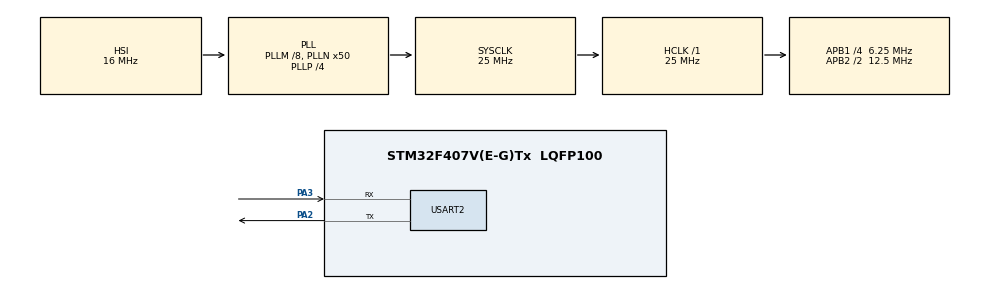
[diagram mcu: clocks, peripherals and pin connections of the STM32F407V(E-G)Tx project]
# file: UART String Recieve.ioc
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Mcu.Family=STM32F4
Mcu.Name=STM32F407V(E-G)Tx
Mcu.Package=LQFP100
NVIC.PriorityGroup=NVIC_PRIORITYGROUP_0
PA2.Mode=Asynchronous
PA2.Signal=USART2_TX
PA3.Mode=Asynchronous
PA3.Signal=USART2_RX
ProjectManager.HeapSize=0x200
ProjectManager.StackSize=0x400
ProjectManager.TargetToolchain=STM32CubeIDE
RCC.48MHZClocksFreq_Value=14285714.285714285
RCC.AHBFreq_Value=25000000
RCC.APB1CLKDivider=RCC_HCLK_DIV4
RCC.APB1Freq_Value=6250000
RCC.APB1TimFreq_Value=12500000
RCC.APB2CLKDivider=RCC_HCLK_DIV2
RCC.APB2Freq_Value=12500000
RCC.APB2TimFreq_Value=25000000
RCC.CortexFreq_Value=25000000
RCC.HCLKFreq_Value=25000000
RCC.HSE_VALUE=8000000
RCC.HSI_VALUE=16000000
RCC.LSE_VALUE=32768
RCC.PLLM=8
RCC.PLLN=50
RCC.PLLP=RCC_PLLP_DIV4
RCC.PLLQ=7
RCC.SYSCLKFreq_VALUE=25000000
RCC.SYSCLKSource=RCC_SYSCLKSOURCE_PLLCLK
RCC.VCOOutputFreq_Value=100000000
USART2.VirtualMode=VM_ASYNC
board=STM32F407G-DISC1

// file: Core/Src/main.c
/* USER CODE BEGIN Header */
/**
  ******************************************************************************
  * @file           : main.c
  * @brief          : Main program body
  ******************************************************************************
  * @attention
  *
  * Copyright (c) 2025 STMicroelectronics.
  * All rights reserved.
  *
  * This software is licensed under terms that can be found in the LICENSE file
  * in the root directory of this software component.
  * If no LICENSE file comes with this software, it is provided AS-IS.
  *
  ******************************************************************************
  */
/* USER CODE END Header */
#include "main.h"
#include<string.h>

/* USER CODE BEGIN Includes */

#define MAX_LEN 100
uint8_t rx_byte;             // single incoming byte
char rx_buffer[MAX_LEN];     // store full string
uint16_t rx_index = 0;       // current position

/* USER CODE END Includes */

UART_HandleTypeDef huart2;

void SystemClock_Config(void);
static void MX_GPIO_Init(void);
static void MX_USART2_UART_Init(void);

int main(void)
{

  /* MCU Configuration--------------------------------------------------------*/

  /* Reset of all peripherals, Initializes the Flash interface and the Systick. */
  HAL_Init();

  /* Configure the system clock */
  SystemClock_Config();

  /* Initialize all configured peripherals */
  MX_GPIO_Init();
  MX_USART2_UART_Init();
  /* USER CODE BEGIN 2 */
  char msg[50] = "Enter Data ...\r\n";
  HAL_UART_Transmit(&huart2, ( uint8_t *)msg,strlen(msg),HAL_MAX_DELAY);
  /* USER CODE END 2 */

  /* Infinite loop */
  /* USER CODE BEGIN WHILE */
  while (1)
  {
      /* Receive one byte (blocking polling) */
      HAL_UART_Receive(&huart2, &rx_byte, 1, HAL_MAX_DELAY);

      /* Echo received byte */
      HAL_UART_Transmit(&huart2, &rx_byte, 1, HAL_MAX_DELAY);

      /* ENTER key handling */
      if (rx_byte == '\r')
      {
          rx_buffer[rx_index] = '\0';   // terminate string

          char msg1[] = "\r\nYou sent: ";
          HAL_UART_Transmit(&huart2, (uint8_t*)msg1, strlen(msg1), HAL_MAX_DELAY);
          HAL_UART_Transmit(&huart2, (uint8_t*)rx_buffer, strlen(rx_buffer), HAL_MAX_DELAY);

          /* Convert to uppercase */
          strupr(rx_buffer);

//          char msg2[] = "\r\nUppercase: ";
//          HAL_UART_Transmit(&huart2, (uint8_t*)msg2, strlen(msg2), HAL_MAX_DELAY);
//          HAL_UART_Transmit(&huart2, (uint8_t*)rx_buffer, strlen(rx_buffer), HAL_MAX_DELAY);

//          uint8_t len = strlen(msg);
//          sprintf(msg, "len = %d\r\n", len);
//          HAL_UART_Transmit(&huart2, (uint8_t *)msg, strlen(msg), HAL_MAX_DELAY);

          char msg3[] = "\r\n";
          HAL_UART_Transmit(&huart2, (uint8_t*)msg3, strlen(msg3), HAL_MAX_DELAY);

          rx_index = 0;   // reset buffer
      }
      else
      {
          /* Store character */
          if (rx_index < MAX_LEN - 1)
          {
              rx_buffer[rx_index++] = rx_byte;
          }
      }
  }

  /* USER CODE END 3 */
}

void SystemClock_Config(void)
{
  RCC_OscInitTypeDef RCC_OscInitStruct = {0};
  RCC_ClkInitTypeDef RCC_ClkInitStruct = {0};

  /** Configure the main internal regulator output voltage
  */
  __HAL_RCC_PWR_CLK_ENABLE();
  __HAL_PWR_VOLTAGESCALING_CONFIG(PWR_REGULATOR_VOLTAGE_SCALE1);

  /** Initializes the RCC Oscillators according to the specified parameters
  * in the RCC_OscInitTypeDef structure.
  */
  RCC_OscInitStruct.OscillatorType = RCC_OSCILLATORTYPE_HSI;
  RCC_OscInitStruct.HSIState = RCC_HSI_ON;
  RCC_OscInitStruct.HSICalibrationValue = RCC_HSICALIBRATION_DEFAULT;
  RCC_OscInitStruct.PLL.PLLState = RCC_PLL_ON;
  RCC_OscInitStruct.PLL.PLLSource = RCC_PLLSOURCE_HSI;
  RCC_OscInitStruct.PLL.PLLM = 8;
  RCC_OscInitStruct.PLL.PLLN = 50;
  RCC_OscInitStruct.PLL.PLLP = RCC_PLLP_DIV4;
  RCC_OscInitStruct.PLL.PLLQ = 7;
  if (HAL_RCC_OscConfig(&RCC_OscInitStruct) != HAL_OK)
  {
    Error_Handler();
  }

  /** Initializes the CPU, AHB and APB buses clocks
  */
  RCC_ClkInitStruct.ClockType = RCC_CLOCKTYPE_HCLK|RCC_CLOCKTYPE_SYSCLK
                              |RCC_CLOCKTYPE_PCLK1|RCC_CLOCKTYPE_PCLK2;
  RCC_ClkInitStruct.SYSCLKSource = RCC_SYSCLKSOURCE_PLLCLK;
  RCC_ClkInitStruct.AHBCLKDivider = RCC_SYSCLK_DIV1;
  RCC_ClkInitStruct.APB1CLKDivider = RCC_HCLK_DIV4;
  RCC_ClkInitStruct.APB2CLKDivider = RCC_HCLK_DIV2;

  if (HAL_RCC_ClockConfig(&RCC_ClkInitStruct, FLASH_LATENCY_0) != HAL_OK)
  {
    Error_Handler();
  }
}

static void MX_USART2_UART_Init(void)
{

  huart2.Instance = USART2;
  huart2.Init.BaudRate = 9600;
  huart2.Init.WordLength = UART_WORDLENGTH_8B;
  huart2.Init.StopBits = UART_STOPBITS_1;
  huart2.Init.Parity = UART_PARITY_NONE;
  huart2.Init.Mode = UART_MODE_TX_RX;
  huart2.Init.HwFlowCtl = UART_HWCONTROL_NONE;
  huart2.Init.OverSampling = UART_OVERSAMPLING_16;
  if (HAL_UART_Init(&huart2) != HAL_OK)
  {
    Error_Handler();
  }

}

static void MX_GPIO_Init(void)
{
  GPIO_InitTypeDef GPIO_InitStruct = {0};

  /* GPIO Ports Clock Enable */
  __HAL_RCC_GPIOA_CLK_ENABLE();
  __HAL_RCC_GPIOD_CLK_ENABLE();

  /*Configure GPIO pin Output Level */
  HAL_GPIO_WritePin(GPIOD, GPIO_PIN_12|GPIO_PIN_13|GPIO_PIN_14|GPIO_PIN_15, GPIO_PIN_RESET);

  /*Configure GPIO pins : PD12 PD13 PD14 PD15 */
  GPIO_InitStruct.Pin = GPIO_PIN_12|GPIO_PIN_13|GPIO_PIN_14|GPIO_PIN_15;
  GPIO_InitStruct.Mode = GPIO_MODE_OUTPUT_PP;
  GPIO_InitStruct.Pull = GPIO_NOPULL;
  GPIO_InitStruct.Speed = GPIO_SPEED_FREQ_LOW;
  HAL_GPIO_Init(GPIOD, &GPIO_InitStruct);

}

void Error_Handler(void)
{
  __disable_irq();
  while (1)
  {
  }
}
